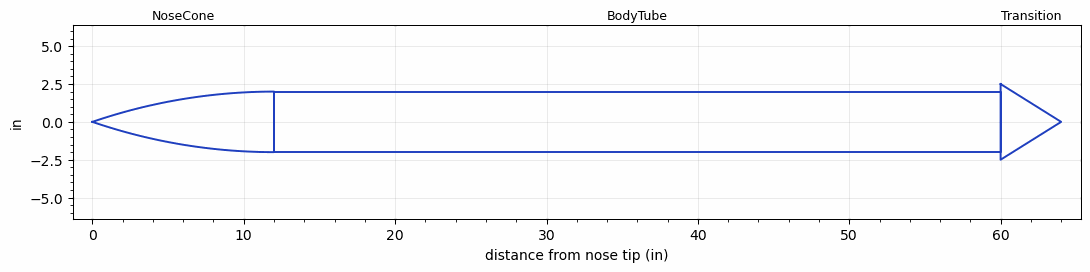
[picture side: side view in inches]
<RASAeroDocument>
 <FileVersion>2</FileVersion>
 <RocketDesign>
  <NoseCone>
   <Length>12.0</Length>
   <Diameter>4.0</Diameter>
   <Shape>Tangent Ogive</Shape>
   <Location>0</Location>
  </NoseCone>
  <BodyTube>
   <Length>48.0</Length>
   <Diameter>4.0</Diameter>
   <Location>12.0</Location>
  </BodyTube>
  <Transition>
   <Length>4.0</Length>
   <FrontDiameter>4.0</FrontDiameter>
   <Diameter>5.0</Diameter>
   <Location>60.0</Location>
  </Transition>
  <Surface>Smooth (Zero Roughness)</Surface>
  <ModifiedBarrowman>False</ModifiedBarrowman>
  <Turbulence>False</Turbulence>
  <UseBooster1>False</UseBooster1>
  <UseBooster2>False</UseBooster2>
  <Comments>Oracle case: transition_expand</Comments>
 </RocketDesign>
 <LaunchSite>
  <Altitude>0</Altitude>
  <Pressure>0</Pressure>
  <RodAngle>0</RodAngle>
  <RodLength>10</RodLength>
  <Temperature>59</Temperature>
  <WindSpeed>0</WindSpeed>
 </LaunchSite>
 <Recovery>
  <Altitude1>1000</Altitude1>
  <DeviceType1>None</DeviceType1>
  <Event1>False</Event1>
  <Size1>1</Size1>
  <EventType1>None</EventType1>
  <CD1>1.33</CD1>
  <Altitude2>1000</Altitude2>
  <DeviceType2>None</DeviceType2>
  <Event2>False</Event2>
  <Size2>1</Size2>
  <EventType2>None</EventType2>
  <CD2>1.33</CD2>
 </Recovery>
</RASAeroDocument>
